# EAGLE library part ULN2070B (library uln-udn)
DRIVER ARRAY

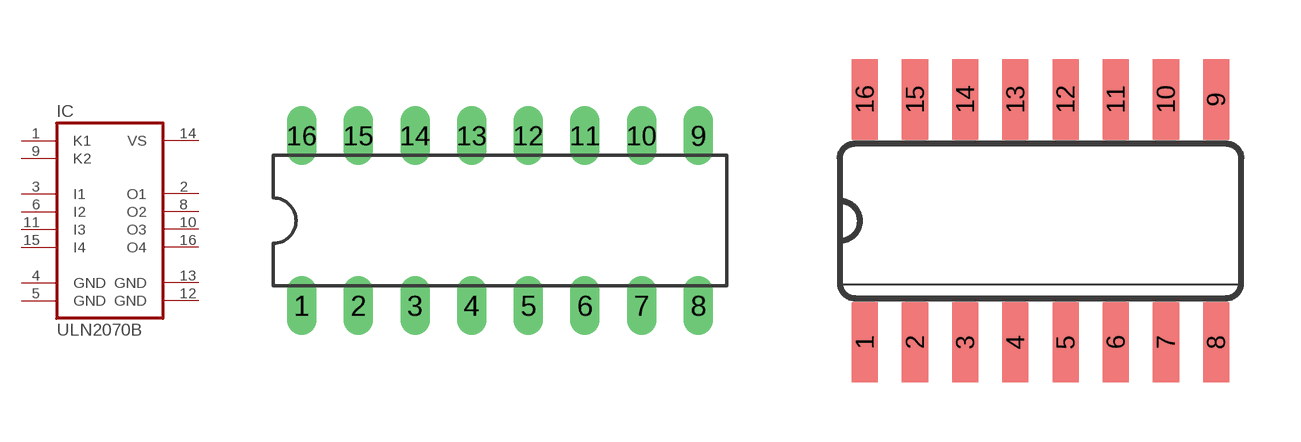
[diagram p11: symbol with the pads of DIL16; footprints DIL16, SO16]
Designator prefix IC

## ULN2070BN  [DIL16]
1  K1  pas
2  O1  oc
3  I1  in
4  GND  pwr
5  GND  pwr
6  I2  in
8  O2  oc
9  K2  pas
10  O3  oc
11  I3  in
12  GND  pwr
13  GND  pwr
14  VS  pwr
15  I4  in
16  O4  oc

## ULN2070BD  [SO16]
Pads as for DIL16

## Footprint DIL16 (pad centres in mm)
Dual In Line Package
drill 0.813 long: 1 -8.89,-3.81; 2 -6.35,-3.81; 3 -3.81,-3.81; 4 -1.27,-3.81; 5 1.27,-3.81; 6 3.81,-3.81; 7 6.35,-3.81; 8 8.89,-3.81; 9 8.89,3.81; 10 6.35,3.81; 11 3.81,3.81; 12 1.27,3.81; 13 -1.27,3.81; 14 -3.81,3.81; 15 -6.35,3.81; 16 -8.89,3.81

## Footprint SO16 (pad centres in mm)
Small Outline Package
smd 0.66 x 2.032: 1 -4.445,-3.073; 2 -3.175,-3.073; 3 -1.905,-3.073; 4 -0.635,-3.073; 5 0.635,-3.073; 6 1.905,-3.073; 7 3.175,-3.073; 8 4.445,-3.073; 9 4.445,3.073; 10 3.175,3.073; 11 1.905,3.073; 12 0.635,3.073; 13 -0.635,3.073; 14 -1.905,3.073; 15 -3.175,3.073; 16 -4.445,3.073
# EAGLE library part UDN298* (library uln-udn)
DRIVER ARRAY Source: Allegro Microsystems Inc. / UDN2981-UDN2984.pdf

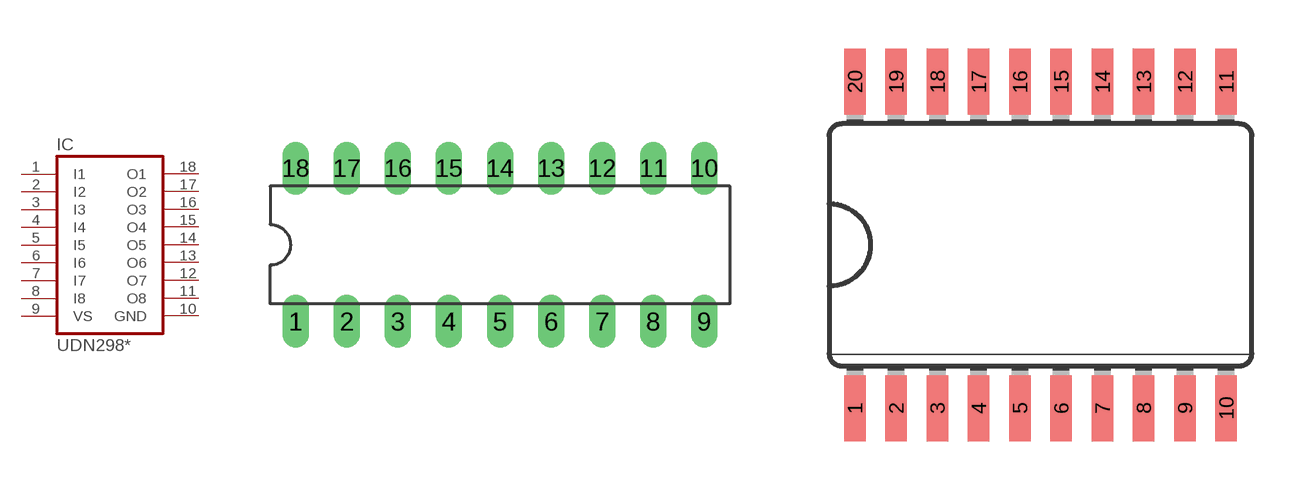
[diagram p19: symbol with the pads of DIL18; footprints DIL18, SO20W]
Designator prefix IC

## UDN2981A, UDN2982A, UDN2983A, UDN2984A  [DIL18]
1  I1  in
2  I2  in
3  I3  in
4  I4  in
5  I5  in
6  I6  in
7  I7  in
8  I8  in
9  VS  pas
10  GND  pwr
11  O8  oc
12  O7  oc
13  O6  oc
14  O5  oc
15  O4  oc
16  O3  oc
17  O2  oc
18  O1  oc

## UDN2981SLW, UDN2982SLW, UDN2983SLW, UDN2984SLW  [SO20W]
1  I1  in
2  I2  in
3  I3  in
4  I4  in
5  I5  in
6  I6  in
7  I7  in
8  I8  in
9  VS  pas
12  GND  pwr
13  O8  oc
14  O7  oc
15  O6  oc
16  O5  oc
17  O4  oc
18  O3  oc
19  O2  oc
20  O1  oc

## UDN2981LW, UDN2982LW, UDN2983LW, UDN2984LW  [SO18W]
Pads as for DIL18

## Footprint DIL18 (pad centres in mm)
Dual In Line Package
drill 0.813 long: 1 -10.16,-3.81; 2 -7.62,-3.81; 3 -5.08,-3.81; 4 -2.54,-3.81; 5 0,-3.81; 6 2.54,-3.81; 7 5.08,-3.81; 8 7.62,-3.81; 9 10.16,-3.81; 10 10.16,3.81; 11 7.62,3.81; 12 5.08,3.81; 13 2.54,3.81; 14 0,3.81; 15 -2.54,3.81; 16 -5.08,3.81; 17 -7.62,3.81; 18 -10.16,3.81

## Footprint SO20W (pad centres in mm)
Small Outline Package wide
smd 0.66 x 2.032: 1 -5.715,-5.029; 2 -4.445,-5.029; 3 -3.175,-5.029; 4 -1.905,-5.029; 5 -0.635,-5.029; 6 0.635,-5.029; 7 1.905,-5.029; 8 3.175,-5.029; 9 4.445,-5.029; 10 5.715,-5.029; 11 5.715,5.029; 12 4.445,5.029; 13 3.175,5.029; 14 1.905,5.029; 15 0.635,5.029; 16 -0.635,5.029; 17 -1.905,5.029; 18 -3.175,5.029; 19 -4.445,5.029; 20 -5.715,5.029

## Footprint SO18W (pad centres in mm)
Small Outline Package wide
smd 0.66 x 2.032: 1 -5.08,-5.029; 2 -3.81,-5.029; 3 -2.54,-5.029; 4 -1.27,-5.029; 5 0,-5.029; 6 1.27,-5.029; 7 2.54,-5.029; 8 3.81,-5.029; 9 5.08,-5.029; 10 5.08,5.029; 11 3.81,5.029; 12 2.54,5.029; 13 1.27,5.029; 14 0,5.029; 15 -1.27,5.029; 16 -2.54,5.029; 17 -3.81,5.029; 18 -5.08,5.029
